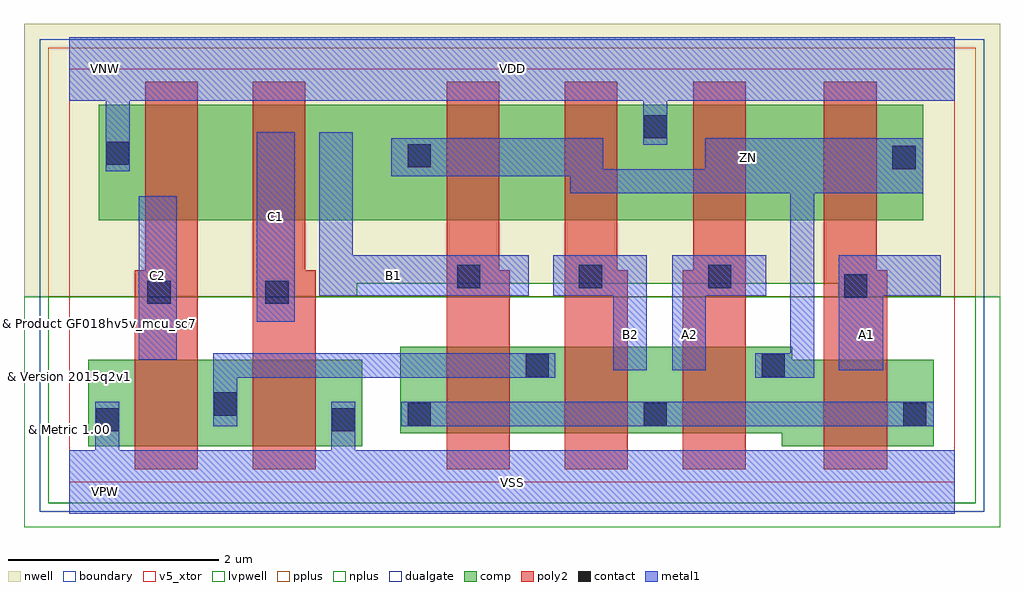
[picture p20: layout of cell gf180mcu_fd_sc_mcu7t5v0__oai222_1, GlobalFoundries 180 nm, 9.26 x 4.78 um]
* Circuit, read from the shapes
.subckt gf180mcu_fd_sc_mcu7t5v0__oai222_1 A1 A2 B1 B2 C1 C2 VDD VNW VSS ZN
XM1 n1 C2 VSS VSUBS nfet_05v0 w=0.82u l=0.6u
XM2 VSS C1 n1 VSUBS nfet_05v0 w=0.82u l=0.6u
XM3 n1 B1 n2 VSUBS nfet_05v0 w=0.82u l=0.6u
XM4 n2 B2 n1 VSUBS nfet_05v0 w=0.82u l=0.6u
XM5 ZN A2 n2 VSUBS nfet_05v0 w=0.82u l=0.6u
XM6 n2 A1 ZN VSUBS nfet_05v0 w=0.82u l=0.6u
XM7 n3 C2 VDD VNW pfet_05v0 w=1.095u l=0.5u
XM8 ZN C1 n3 VNW pfet_05v0 w=1.095u l=0.5u
XM9 n4 B1 ZN VNW pfet_05v0 w=1.095u l=0.5u
XM10 VDD B2 n4 VNW pfet_05v0 w=1.095u l=0.5u
XM11 n5 A2 VDD VNW pfet_05v0 w=1.095u l=0.5u
XM12 ZN A1 n5 VNW pfet_05v0 w=1.095u l=0.5u
.ends

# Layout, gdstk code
import gdstk
lib = gdstk.Library(unit=1e-6, precision=1e-09)
def R(c, l, rs):  # rectangles x0, y0, x1, y1
    for r in rs: c.add(gdstk.rectangle(r[:2], r[2:], *l))
def P(c, l, *ps):  # polygons
    for p in ps: c.add(gdstk.Polygon(p, *l))
boundary = (0, 0)
nwell = (21, 0)
comp = (22, 0)
poly2 = (30, 0)
pplus = (31, 0)
nplus = (32, 0)
contact = (33, 0)
metal1 = (34, 0)
dualgate = (55, 0)
v5_xtor = (112, 1)
lvpwell = (204, 0)

gf180mcu_fd_sc_mcu7t5v0_ = lib.new_cell('gf180mcu_fd_sc_mcu7t5v0__oai222_1')
R(gf180mcu_fd_sc_mcu7t5v0_, boundary, [(0,0,8.4,3.92)])
P(gf180mcu_fd_sc_mcu7t5v0_, nwell, [(-0.43,1.76),(-0.43,4.35),(8.83,4.35),(8.83,1.76),(7.3,1.76),(7.3,1.885),(2.725,1.885),(2.725,1.76)])
R(gf180mcu_fd_sc_mcu7t5v0_, comp, [(0.18,0.34,2.78,1.16), (0.28,2.485,8.1,3.58)])
P(gf180mcu_fd_sc_mcu7t5v0_, comp, [(6.76,0.34),(6.76,0.465),(3.14,0.465),(3.14,1.285),(6.86,1.285),(6.86,1.16),(8.2,1.16),(8.2,0.34)])
P(gf180mcu_fd_sc_mcu7t5v0_, poly2, [(0.62,0.12),(0.62,2.01),(0.72,2.01),(0.72,3.8),(1.22,3.8),(1.22,0.12)],
  [(1.74,0.12),(1.74,3.8),(2.24,3.8),(2.24,2.01),(2.34,2.01),(2.34,0.12)],
  [(3.58,0.12),(3.58,3.8),(4.08,3.8),(4.08,2.01),(4.18,2.01),(4.18,0.12)],
  [(4.7,0.12),(4.7,3.8),(5.2,3.8),(5.2,2.01),(5.3,2.01),(5.3,0.12)],
  [(5.82,0.12),(5.82,2.01),(5.92,2.01),(5.92,3.8),(6.42,3.8),(6.42,0.12)],
  [(7.16,0.12),(7.16,3.8),(7.66,3.8),(7.66,2.01),(7.76,2.01),(7.76,0.12)])
R(gf180mcu_fd_sc_mcu7t5v0_, pplus, [(-0.2,1.76,8.6,4.12)])
R(gf180mcu_fd_sc_mcu7t5v0_, nplus, [(-0.2,-0.2,8.6,1.76)])
R(gf180mcu_fd_sc_mcu7t5v0_, contact, [(0.25,0.48,0.47,0.7), (2.49,0.48,2.71,0.7), (3.21,0.535,3.43,0.755), (5.45,0.535,5.67,0.755), (7.91,0.535,8.13,0.755), (1.37,0.63,1.59,0.85), (4.33,0.995,4.55,1.215), (6.57,0.995,6.79,1.215), (0.74,1.69,0.96,1.91), (1.86,1.69,2.08,1.91), (7.35,1.75,7.57,1.97), (3.68,1.84,3.9,2.06), (4.835,1.84,5.055,2.06), (6.06,1.84,6.28,2.06), (7.81,2.97,8.03,3.19), (3.21,2.985,3.43,3.205), (0.35,3.01,0.57,3.23), (5.45,3.26,5.67,3.48)])
R(gf180mcu_fd_sc_mcu7t5v0_, metal1, [(3.15,0.53,8.2,0.76), (0.66,1.16,1.02,2.71), (1.78,1.52,2.14,3.32)])
P(gf180mcu_fd_sc_mcu7t5v0_, metal1, [(2.37,1.77),(2.37,3.32),(2.69,3.32),(2.69,2.15),(4.36,2.15),(4.36,1.77)],
  [(1.365,0.53),(1.365,1.22),(4.61,1.22),(4.61,0.99),(1.595,0.99),(1.595,0.53)],
  [(5.16,1.06),(5.16,1.77),(4.59,1.77),(4.59,2.15),(5.48,2.15),(5.48,1.06)],
  [(5.72,1.06),(5.72,2.15),(6.61,2.15),(6.61,1.77),(6.04,1.77),(6.04,1.06)],
  [(6.51,0.99),(6.51,1.22),(6.84,1.22),(6.84,2.74),(4.755,2.74),(4.755,2.9),(3.055,2.9),(3.055,3.26),(5.065,3.26),(5.065,2.97),(6.035,2.97),(6.035,3.26),(8.1,3.26),(8.1,2.74),(7.07,2.74),(7.07,0.99)],
  [(7.3,1.06),(7.3,2.15),(8.27,2.15),(8.27,1.77),(7.72,1.77),(7.72,1.06)],
  [(0,-0.3),(0,0.3),(0.245,0.3),(0.245,0.76),(0.475,0.76),(0.475,0.3),(2.485,0.3),(2.485,0.76),(2.715,0.76),(2.715,0.3),(8.4,0.3),(8.4,-0.3)],
  [(0.345,2.95),(0.345,3.62),(0,3.62),(0,4.22),(8.4,4.22),(8.4,3.62),(5.675,3.62),(5.675,3.2),(5.445,3.2),(5.445,3.62),(0.575,3.62),(0.575,2.95)])
R(gf180mcu_fd_sc_mcu7t5v0_, dualgate, [(-0.28,-0.28,8.68,4.2)])
R(gf180mcu_fd_sc_mcu7t5v0_, v5_xtor, [(0,0,8.4,3.92)])
P(gf180mcu_fd_sc_mcu7t5v0_, lvpwell, [(-0.43,-0.43),(-0.43,1.76),(2.725,1.76),(2.725,1.885),(7.3,1.885),(7.3,1.76),(8.83,1.76),(8.83,-0.43)])
gf180mcu_fd_sc_mcu7t5v0_.add(gdstk.Label('B1', (3.08,1.96), layer=34, texttype=10))
gf180mcu_fd_sc_mcu7t5v0_.add(gdstk.Label('B2', (5.32,1.4), layer=34, texttype=10))
gf180mcu_fd_sc_mcu7t5v0_.add(gdstk.Label('C1', (1.96,2.52), layer=34, texttype=10))
gf180mcu_fd_sc_mcu7t5v0_.add(gdstk.Label('C2', (0.84,1.96), layer=34, texttype=10))
gf180mcu_fd_sc_mcu7t5v0_.add(gdstk.Label('VDD', (4.2,3.92), layer=34, texttype=10))
gf180mcu_fd_sc_mcu7t5v0_.add(gdstk.Label('VSS', (4.2,0), layer=34, texttype=10))
gf180mcu_fd_sc_mcu7t5v0_.add(gdstk.Label('ZN', (6.44,3.08), layer=34, texttype=10))
gf180mcu_fd_sc_mcu7t5v0_.add(gdstk.Label('A1', (7.56,1.4), layer=34, texttype=10))
gf180mcu_fd_sc_mcu7t5v0_.add(gdstk.Label('A2', (5.88,1.4), layer=34, texttype=10))
gf180mcu_fd_sc_mcu7t5v0_.add(gdstk.Label('& Vendor GLOBALFOUNDRIES', (0,2), layer=63, texttype=63))
gf180mcu_fd_sc_mcu7t5v0_.add(gdstk.Label('& Product GF018hv5v_mcu_sc7', (0,1.5), layer=63, texttype=63))
gf180mcu_fd_sc_mcu7t5v0_.add(gdstk.Label('& Version 2015q2v1', (0,1), layer=63, texttype=63))
gf180mcu_fd_sc_mcu7t5v0_.add(gdstk.Label('& Metric 1.00', (0,0.5), layer=63, texttype=63))
gf180mcu_fd_sc_mcu7t5v0_.add(gdstk.Label('VNW', (0.345,3.92), layer=21, texttype=10))
gf180mcu_fd_sc_mcu7t5v0_.add(gdstk.Label('VPW', (0.34,-0.085), layer=204, texttype=10))

lib.write_gds('gf180mcu_fd_sc_mcu7t5v0__oai222_1.gds')
